# Generated by innovus_enablement/scripts/gen_fakeram.py: abstract 64x21 SRAM.
# Geometry is an assumption (see script header), not PDK data.
VERSION 5.8 ;
BUSBITCHARS "[]" ;
DIVIDERCHAR "/" ;

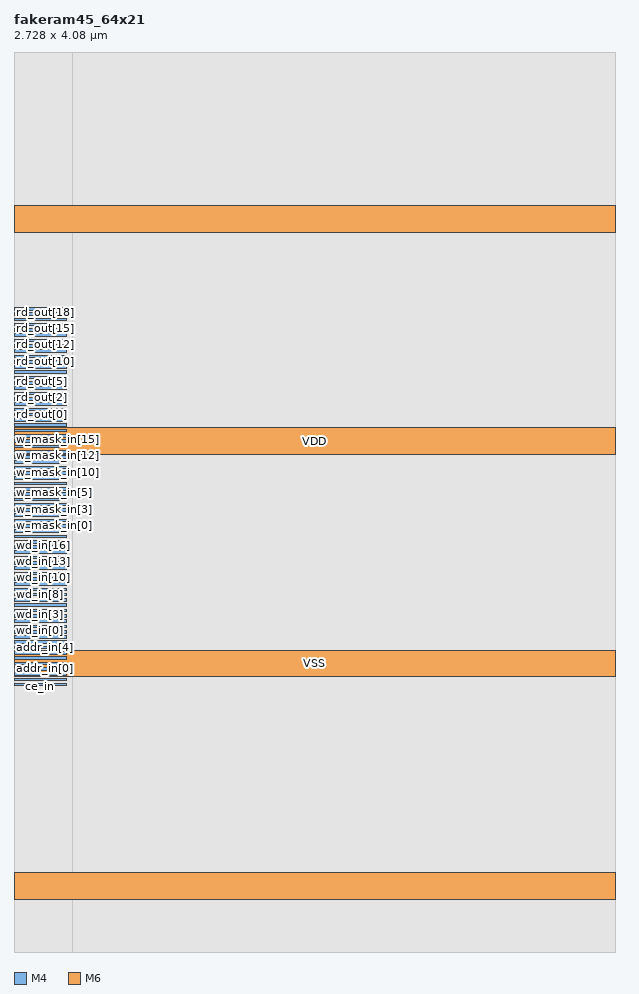
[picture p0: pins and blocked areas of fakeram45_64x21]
MACRO fakeram45_64x21
  CLASS BLOCK ;
  FOREIGN fakeram45_64x21 0 0 ;
  ORIGIN 0 0 ;
  SIZE 2.7280 BY 4.0800 ;
  SYMMETRY X Y R90 ;
  PIN clk
    DIRECTION INPUT ;
    USE CLOCK ;
    PORT
      LAYER M4 ;
        RECT 0 1.2060 0.2400 1.2180 ;
    END
  END clk
  PIN ce_in
    DIRECTION INPUT ;
    USE SIGNAL ;
    PORT
      LAYER M4 ;
        RECT 0 1.2300 0.2400 1.2420 ;
    END
  END ce_in
  PIN we_in
    DIRECTION INPUT ;
    USE SIGNAL ;
    PORT
      LAYER M4 ;
        RECT 0 1.2540 0.2400 1.2660 ;
    END
  END we_in
  PIN addr_in[0]
    DIRECTION INPUT ;
    USE SIGNAL ;
    PORT
      LAYER M4 ;
        RECT 0 1.2780 0.2400 1.2900 ;
    END
  END addr_in[0]
  PIN addr_in[1]
    DIRECTION INPUT ;
    USE SIGNAL ;
    PORT
      LAYER M4 ;
        RECT 0 1.3020 0.2400 1.3140 ;
    END
  END addr_in[1]
  PIN addr_in[2]
    DIRECTION INPUT ;
    USE SIGNAL ;
    PORT
      LAYER M4 ;
        RECT 0 1.3260 0.2400 1.3380 ;
    END
  END addr_in[2]
  PIN addr_in[3]
    DIRECTION INPUT ;
    USE SIGNAL ;
    PORT
      LAYER M4 ;
        RECT 0 1.3500 0.2400 1.3620 ;
    END
  END addr_in[3]
  PIN addr_in[4]
    DIRECTION INPUT ;
    USE SIGNAL ;
    PORT
      LAYER M4 ;
        RECT 0 1.3740 0.2400 1.3860 ;
    END
  END addr_in[4]
  PIN addr_in[5]
    DIRECTION INPUT ;
    USE SIGNAL ;
    PORT
      LAYER M4 ;
        RECT 0 1.3980 0.2400 1.4100 ;
    END
  END addr_in[5]
  PIN wd_in[0]
    DIRECTION INPUT ;
    USE SIGNAL ;
    PORT
      LAYER M4 ;
        RECT 0 1.4220 0.2400 1.4340 ;
    END
  END wd_in[0]
  PIN wd_in[1]
    DIRECTION INPUT ;
    USE SIGNAL ;
    PORT
      LAYER M4 ;
        RECT 0 1.4460 0.2400 1.4580 ;
    END
  END wd_in[1]
  PIN wd_in[2]
    DIRECTION INPUT ;
    USE SIGNAL ;
    PORT
      LAYER M4 ;
        RECT 0 1.4700 0.2400 1.4820 ;
    END
  END wd_in[2]
  PIN wd_in[3]
    DIRECTION INPUT ;
    USE SIGNAL ;
    PORT
      LAYER M4 ;
        RECT 0 1.4940 0.2400 1.5060 ;
    END
  END wd_in[3]
  PIN wd_in[4]
    DIRECTION INPUT ;
    USE SIGNAL ;
    PORT
      LAYER M4 ;
        RECT 0 1.5180 0.2400 1.5300 ;
    END
  END wd_in[4]
  PIN wd_in[5]
    DIRECTION INPUT ;
    USE SIGNAL ;
    PORT
      LAYER M4 ;
        RECT 0 1.5420 0.2400 1.5540 ;
    END
  END wd_in[5]
  PIN wd_in[6]
    DIRECTION INPUT ;
    USE SIGNAL ;
    PORT
      LAYER M4 ;
        RECT 0 1.5660 0.2400 1.5780 ;
    END
  END wd_in[6]
  PIN wd_in[7]
    DIRECTION INPUT ;
    USE SIGNAL ;
    PORT
      LAYER M4 ;
        RECT 0 1.5900 0.2400 1.6020 ;
    END
  END wd_in[7]
  PIN wd_in[8]
    DIRECTION INPUT ;
    USE SIGNAL ;
    PORT
      LAYER M4 ;
        RECT 0 1.6140 0.2400 1.6260 ;
    END
  END wd_in[8]
  PIN wd_in[9]
    DIRECTION INPUT ;
    USE SIGNAL ;
    PORT
      LAYER M4 ;
        RECT 0 1.6380 0.2400 1.6500 ;
    END
  END wd_in[9]
  PIN wd_in[10]
    DIRECTION INPUT ;
    USE SIGNAL ;
    PORT
      LAYER M4 ;
        RECT 0 1.6620 0.2400 1.6740 ;
    END
  END wd_in[10]
  PIN wd_in[11]
    DIRECTION INPUT ;
    USE SIGNAL ;
    PORT
      LAYER M4 ;
        RECT 0 1.6860 0.2400 1.6980 ;
    END
  END wd_in[11]
  PIN wd_in[12]
    DIRECTION INPUT ;
    USE SIGNAL ;
    PORT
      LAYER M4 ;
        RECT 0 1.7100 0.2400 1.7220 ;
    END
  END wd_in[12]
  PIN wd_in[13]
    DIRECTION INPUT ;
    USE SIGNAL ;
    PORT
      LAYER M4 ;
        RECT 0 1.7340 0.2400 1.7460 ;
    END
  END wd_in[13]
  PIN wd_in[14]
    DIRECTION INPUT ;
    USE SIGNAL ;
    PORT
      LAYER M4 ;
        RECT 0 1.7580 0.2400 1.7700 ;
    END
  END wd_in[14]
  PIN wd_in[15]
    DIRECTION INPUT ;
    USE SIGNAL ;
    PORT
      LAYER M4 ;
        RECT 0 1.7820 0.2400 1.7940 ;
    END
  END wd_in[15]
  PIN wd_in[16]
    DIRECTION INPUT ;
    USE SIGNAL ;
    PORT
      LAYER M4 ;
        RECT 0 1.8060 0.2400 1.8180 ;
    END
  END wd_in[16]
  PIN wd_in[17]
    DIRECTION INPUT ;
    USE SIGNAL ;
    PORT
      LAYER M4 ;
        RECT 0 1.8300 0.2400 1.8420 ;
    END
  END wd_in[17]
  PIN wd_in[18]
    DIRECTION INPUT ;
    USE SIGNAL ;
    PORT
      LAYER M4 ;
        RECT 0 1.8540 0.2400 1.8660 ;
    END
  END wd_in[18]
  PIN wd_in[19]
    DIRECTION INPUT ;
    USE SIGNAL ;
    PORT
      LAYER M4 ;
        RECT 0 1.8780 0.2400 1.8900 ;
    END
  END wd_in[19]
  PIN wd_in[20]
    DIRECTION INPUT ;
    USE SIGNAL ;
    PORT
      LAYER M4 ;
        RECT 0 1.9020 0.2400 1.9140 ;
    END
  END wd_in[20]
  PIN w_mask_in[0]
    DIRECTION INPUT ;
    USE SIGNAL ;
    PORT
      LAYER M4 ;
        RECT 0 1.9260 0.2400 1.9380 ;
    END
  END w_mask_in[0]
  PIN w_mask_in[1]
    DIRECTION INPUT ;
    USE SIGNAL ;
    PORT
      LAYER M4 ;
        RECT 0 1.9500 0.2400 1.9620 ;
    END
  END w_mask_in[1]
  PIN w_mask_in[2]
    DIRECTION INPUT ;
    USE SIGNAL ;
    PORT
      LAYER M4 ;
        RECT 0 1.9740 0.2400 1.9860 ;
    END
  END w_mask_in[2]
  PIN w_mask_in[3]
    DIRECTION INPUT ;
    USE SIGNAL ;
    PORT
      LAYER M4 ;
        RECT 0 1.9980 0.2400 2.0100 ;
    END
  END w_mask_in[3]
  PIN w_mask_in[4]
    DIRECTION INPUT ;
    USE SIGNAL ;
    PORT
      LAYER M4 ;
        RECT 0 2.0220 0.2400 2.0340 ;
    END
  END w_mask_in[4]
  PIN w_mask_in[5]
    DIRECTION INPUT ;
    USE SIGNAL ;
    PORT
      LAYER M4 ;
        RECT 0 2.0460 0.2400 2.0580 ;
    END
  END w_mask_in[5]
  PIN w_mask_in[6]
    DIRECTION INPUT ;
    USE SIGNAL ;
    PORT
      LAYER M4 ;
        RECT 0 2.0700 0.2400 2.0820 ;
    END
  END w_mask_in[6]
  PIN w_mask_in[7]
    DIRECTION INPUT ;
    USE SIGNAL ;
    PORT
      LAYER M4 ;
        RECT 0 2.0940 0.2400 2.1060 ;
    END
  END w_mask_in[7]
  PIN w_mask_in[8]
    DIRECTION INPUT ;
    USE SIGNAL ;
    PORT
      LAYER M4 ;
        RECT 0 2.1180 0.2400 2.1300 ;
    END
  END w_mask_in[8]
  PIN w_mask_in[9]
    DIRECTION INPUT ;
    USE SIGNAL ;
    PORT
      LAYER M4 ;
        RECT 0 2.1420 0.2400 2.1540 ;
    END
  END w_mask_in[9]
  PIN w_mask_in[10]
    DIRECTION INPUT ;
    USE SIGNAL ;
    PORT
      LAYER M4 ;
        RECT 0 2.1660 0.2400 2.1780 ;
    END
  END w_mask_in[10]
  PIN w_mask_in[11]
    DIRECTION INPUT ;
    USE SIGNAL ;
    PORT
      LAYER M4 ;
        RECT 0 2.1900 0.2400 2.2020 ;
    END
  END w_mask_in[11]
  PIN w_mask_in[12]
    DIRECTION INPUT ;
    USE SIGNAL ;
    PORT
      LAYER M4 ;
        RECT 0 2.2140 0.2400 2.2260 ;
    END
  END w_mask_in[12]
  PIN w_mask_in[13]
    DIRECTION INPUT ;
    USE SIGNAL ;
    PORT
      LAYER M4 ;
        RECT 0 2.2380 0.2400 2.2500 ;
    END
  END w_mask_in[13]
  PIN w_mask_in[14]
    DIRECTION INPUT ;
    USE SIGNAL ;
    PORT
      LAYER M4 ;
        RECT 0 2.2620 0.2400 2.2740 ;
    END
  END w_mask_in[14]
  PIN w_mask_in[15]
    DIRECTION INPUT ;
    USE SIGNAL ;
    PORT
      LAYER M4 ;
        RECT 0 2.2860 0.2400 2.2980 ;
    END
  END w_mask_in[15]
  PIN w_mask_in[16]
    DIRECTION INPUT ;
    USE SIGNAL ;
    PORT
      LAYER M4 ;
        RECT 0 2.3100 0.2400 2.3220 ;
    END
  END w_mask_in[16]
  PIN w_mask_in[17]
    DIRECTION INPUT ;
    USE SIGNAL ;
    PORT
      LAYER M4 ;
        RECT 0 2.3340 0.2400 2.3460 ;
    END
  END w_mask_in[17]
  PIN w_mask_in[18]
    DIRECTION INPUT ;
    USE SIGNAL ;
    PORT
      LAYER M4 ;
        RECT 0 2.3580 0.2400 2.3700 ;
    END
  END w_mask_in[18]
  PIN w_mask_in[19]
    DIRECTION INPUT ;
    USE SIGNAL ;
    PORT
      LAYER M4 ;
        RECT 0 2.3820 0.2400 2.3940 ;
    END
  END w_mask_in[19]
  PIN w_mask_in[20]
    DIRECTION INPUT ;
    USE SIGNAL ;
    PORT
      LAYER M4 ;
        RECT 0 2.4060 0.2400 2.4180 ;
    END
  END w_mask_in[20]
  PIN rd_out[0]
    DIRECTION OUTPUT ;
    USE SIGNAL ;
    PORT
      LAYER M4 ;
        RECT 0 2.4300 0.2400 2.4420 ;
    END
  END rd_out[0]
  PIN rd_out[1]
    DIRECTION OUTPUT ;
    USE SIGNAL ;
    PORT
      LAYER M4 ;
        RECT 0 2.4540 0.2400 2.4660 ;
    END
  END rd_out[1]
  PIN rd_out[2]
    DIRECTION OUTPUT ;
    USE SIGNAL ;
    PORT
      LAYER M4 ;
        RECT 0 2.4780 0.2400 2.4900 ;
    END
  END rd_out[2]
  PIN rd_out[3]
    DIRECTION OUTPUT ;
    USE SIGNAL ;
    PORT
      LAYER M4 ;
        RECT 0 2.5020 0.2400 2.5140 ;
    END
  END rd_out[3]
  PIN rd_out[4]
    DIRECTION OUTPUT ;
    USE SIGNAL ;
    PORT
      LAYER M4 ;
        RECT 0 2.5260 0.2400 2.5380 ;
    END
  END rd_out[4]
  PIN rd_out[5]
    DIRECTION OUTPUT ;
    USE SIGNAL ;
    PORT
      LAYER M4 ;
        RECT 0 2.5500 0.2400 2.5620 ;
    END
  END rd_out[5]
  PIN rd_out[6]
    DIRECTION OUTPUT ;
    USE SIGNAL ;
    PORT
      LAYER M4 ;
        RECT 0 2.5740 0.2400 2.5860 ;
    END
  END rd_out[6]
  PIN rd_out[7]
    DIRECTION OUTPUT ;
    USE SIGNAL ;
    PORT
      LAYER M4 ;
        RECT 0 2.5980 0.2400 2.6100 ;
    END
  END rd_out[7]
  PIN rd_out[8]
    DIRECTION OUTPUT ;
    USE SIGNAL ;
    PORT
      LAYER M4 ;
        RECT 0 2.6220 0.2400 2.6340 ;
    END
  END rd_out[8]
  PIN rd_out[9]
    DIRECTION OUTPUT ;
    USE SIGNAL ;
    PORT
      LAYER M4 ;
        RECT 0 2.6460 0.2400 2.6580 ;
    END
  END rd_out[9]
  PIN rd_out[10]
    DIRECTION OUTPUT ;
    USE SIGNAL ;
    PORT
      LAYER M4 ;
        RECT 0 2.6700 0.2400 2.6820 ;
    END
  END rd_out[10]
  PIN rd_out[11]
    DIRECTION OUTPUT ;
    USE SIGNAL ;
    PORT
      LAYER M4 ;
        RECT 0 2.6940 0.2400 2.7060 ;
    END
  END rd_out[11]
  PIN rd_out[12]
    DIRECTION OUTPUT ;
    USE SIGNAL ;
    PORT
      LAYER M4 ;
        RECT 0 2.7180 0.2400 2.7300 ;
    END
  END rd_out[12]
  PIN rd_out[13]
    DIRECTION OUTPUT ;
    USE SIGNAL ;
    PORT
      LAYER M4 ;
        RECT 0 2.7420 0.2400 2.7540 ;
    END
  END rd_out[13]
  PIN rd_out[14]
    DIRECTION OUTPUT ;
    USE SIGNAL ;
    PORT
      LAYER M4 ;
        RECT 0 2.7660 0.2400 2.7780 ;
    END
  END rd_out[14]
  PIN rd_out[15]
    DIRECTION OUTPUT ;
    USE SIGNAL ;
    PORT
      LAYER M4 ;
        RECT 0 2.7900 0.2400 2.8020 ;
    END
  END rd_out[15]
  PIN rd_out[16]
    DIRECTION OUTPUT ;
    USE SIGNAL ;
    PORT
      LAYER M4 ;
        RECT 0 2.8140 0.2400 2.8260 ;
    END
  END rd_out[16]
  PIN rd_out[17]
    DIRECTION OUTPUT ;
    USE SIGNAL ;
    PORT
      LAYER M4 ;
        RECT 0 2.8380 0.2400 2.8500 ;
    END
  END rd_out[17]
  PIN rd_out[18]
    DIRECTION OUTPUT ;
    USE SIGNAL ;
    PORT
      LAYER M4 ;
        RECT 0 2.8620 0.2400 2.8740 ;
    END
  END rd_out[18]
  PIN rd_out[19]
    DIRECTION OUTPUT ;
    USE SIGNAL ;
    PORT
      LAYER M4 ;
        RECT 0 2.8860 0.2400 2.8980 ;
    END
  END rd_out[19]
  PIN rd_out[20]
    DIRECTION OUTPUT ;
    USE SIGNAL ;
    PORT
      LAYER M4 ;
        RECT 0 2.9100 0.2400 2.9220 ;
    END
  END rd_out[20]
  PIN VDD
    DIRECTION INOUT ;
    USE POWER ;
    PORT
      LAYER M6 ;
        RECT 0 0.2400 2.7280 0.3600 ;
        RECT 0 2.2560 2.7280 2.3760 ;
    END
  END VDD
  PIN VSS
    DIRECTION INOUT ;
    USE GROUND ;
    PORT
      LAYER M6 ;
        RECT 0 1.2480 2.7280 1.3680 ;
        RECT 0 3.2640 2.7280 3.3840 ;
    END
  END VSS
  OBS
    LAYER M0 ;
      RECT 0 0 2.7280 4.0800 ;
    LAYER M1 ;
      RECT 0 0 2.7280 4.0800 ;
    LAYER M2 ;
      RECT 0 0 2.7280 4.0800 ;
    LAYER M3 ;
      RECT 0 0 2.7280 4.0800 ;
    LAYER VIA0 ;
      RECT 0 0 2.7280 4.0800 ;
    LAYER VIA1 ;
      RECT 0 0 2.7280 4.0800 ;
    LAYER VIA2 ;
      RECT 0 0 2.7280 4.0800 ;
    LAYER VIA3 ;
      RECT 0 0 2.7280 4.0800 ;
    LAYER M4 ;
      RECT 0.2640 0 2.7280 4.0800 ;
  END
END fakeram45_64x21

END LIBRARY
